VERSION 5.7 ;
  NOWIREEXTENSIONATPIN ON ;
  DIVIDERCHAR "/" ;
  BUSBITCHARS "[]" ;
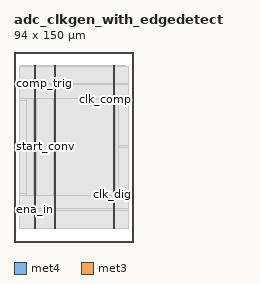
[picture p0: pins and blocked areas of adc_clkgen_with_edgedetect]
MACRO adc_clkgen_with_edgedetect
  CLASS BLOCK ;
  FOREIGN adc_clkgen_with_edgedetect ;
  ORIGIN 0.000 0.000 ;
  SIZE 94.000 BY 150.000 ;
  PIN VGND
    DIRECTION INOUT ;
    USE GROUND ;
    PORT
      LAYER met4 ;
        RECT 31.670 10.640 32.670 138.960 ;
    END
  END VGND
  PIN VPWR
    DIRECTION INOUT ;
    USE POWER ;
    PORT
      LAYER met4 ;
        RECT 16.020 10.640 17.020 138.960 ;
    END
    PORT
      LAYER met4 ;
        RECT 78.620 10.640 79.620 138.960 ;
    END
  END VPWR
  PIN clk_comp
    DIRECTION OUTPUT TRISTATE ;
    USE SIGNAL ;
    PORT
      LAYER met3 ;
        RECT 90.000 112.240 94.000 112.840 ;
    END
  END clk_comp
  PIN clk_dig
    DIRECTION OUTPUT TRISTATE ;
    USE SIGNAL ;
    PORT
      LAYER met3 ;
        RECT 90.000 37.440 94.000 38.040 ;
    END
  END clk_dig
  PIN comp_trig
    DIRECTION INPUT ;
    USE SIGNAL ;
    PORT
      LAYER met3 ;
        RECT 0.000 124.480 4.000 125.080 ;
    END
  END comp_trig
  PIN ena_in
    DIRECTION INPUT ;
    USE SIGNAL ;
    PORT
      LAYER met3 ;
        RECT 0.000 25.200 4.000 25.800 ;
    END
  END ena_in
  PIN start_conv
    DIRECTION INPUT ;
    USE SIGNAL ;
    PORT
      LAYER met3 ;
        RECT 0.000 74.840 4.000 75.440 ;
    END
  END start_conv
  OBS
      LAYER li1 ;
        RECT 5.520 10.795 88.320 138.805 ;
      LAYER met1 ;
        RECT 5.520 10.640 88.320 138.960 ;
      LAYER met2 ;
        RECT 6.540 10.695 82.700 138.905 ;
      LAYER met3 ;
        RECT 4.000 125.480 90.000 138.885 ;
        RECT 4.400 124.080 90.000 125.480 ;
        RECT 4.000 113.240 90.000 124.080 ;
        RECT 4.000 111.840 89.600 113.240 ;
        RECT 4.000 75.840 90.000 111.840 ;
        RECT 4.400 74.440 90.000 75.840 ;
        RECT 4.000 38.440 90.000 74.440 ;
        RECT 4.000 37.040 89.600 38.440 ;
        RECT 4.000 26.200 90.000 37.040 ;
        RECT 4.400 24.800 90.000 26.200 ;
        RECT 4.000 10.715 90.000 24.800 ;
      LAYER met4 ;
        RECT 9.630 36.430 15.620 113.110 ;
        RECT 17.420 36.430 31.270 113.110 ;
        RECT 33.070 36.430 78.220 113.110 ;
        RECT 80.020 36.430 82.370 113.110 ;
  END
END adc_clkgen_with_edgedetect
END LIBRARY

